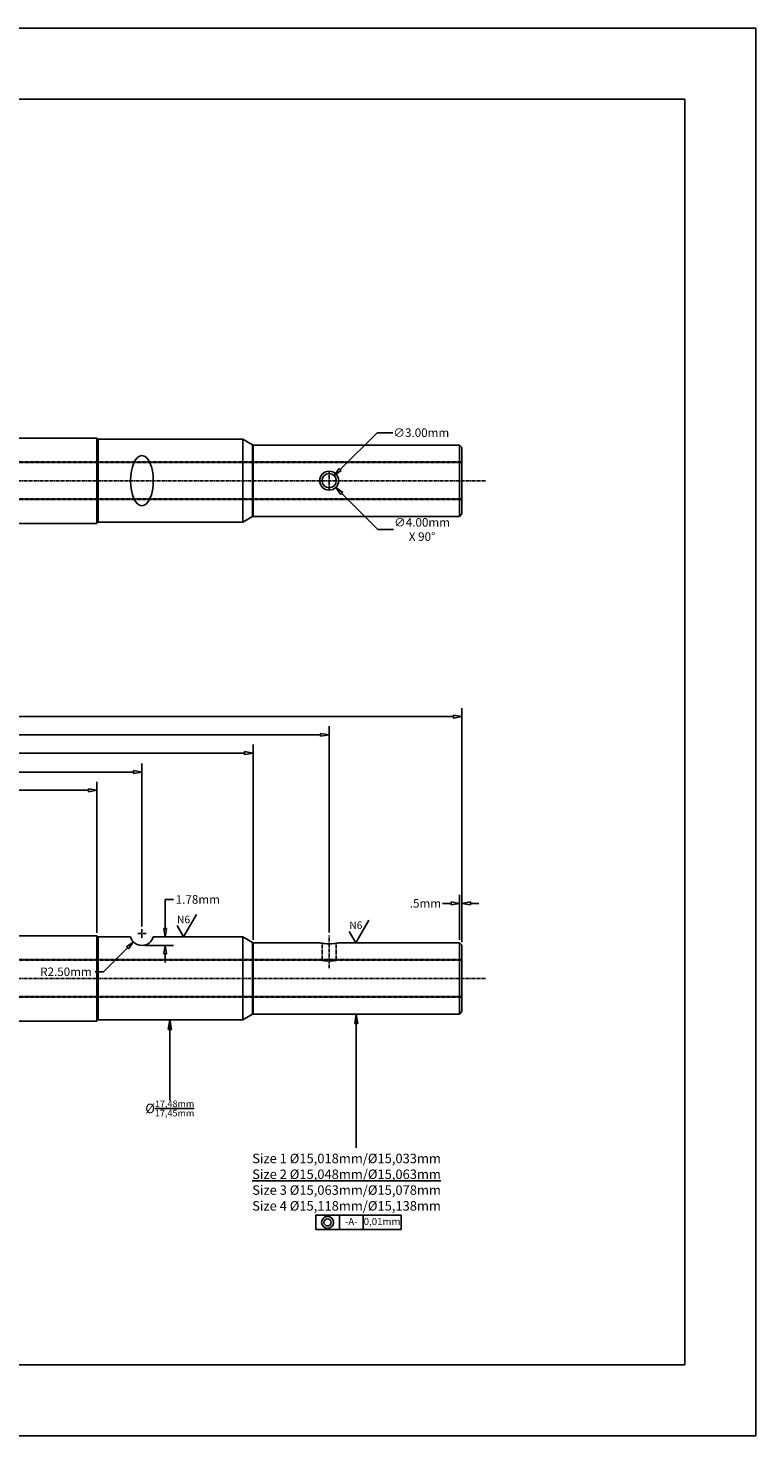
# Model space of a CAD drawing. Units: inches. Extents: x 0 to 420, y 0 to 297.
# Drawn here: x 266 to 420, y 0 to 297 of the extents above; entities that cross this region are included whole.
import ezdxf
from ezdxf.enums import TextEntityAlignment as Align

# ---------------------------------------------------------------- set-up
doc = ezdxf.new("R2010")
doc.units = ezdxf.units.IN
doc.header["$MEASUREMENT"] = 0
doc.linetypes.add('CENTER2', pattern=[1.125, 0.75, -0.125, 0.125, -0.125])
doc.linetypes.add('HIDDEN2', pattern=[0.1875, 0.125, -0.0625])
for name, color, linetype in [('CENTER', 1, 'CENTER2'), ('CENTERLINE', 1, 'CENTER2'), ('HIDDEN', 5, 'HIDDEN2'), ('TEXT', 5, 'Continuous')]:
    doc.layers.add(name, color=color, linetype=linetype)
doc.dimstyles.get("Standard").update_dxf_attribs({"dimscale": 10, "dimtxt": 0.18, "dimasz": 0.18, "dimexe": 0.18, "dimexo": 0.0625, "dimgap": 0.09, "dimtad": 0, "dimtih": 1, "dimtoh": 1, "dimdec": 4, "dimzin": 0, "dimdsep": 46, "dimtxsty": 'Standard', "dimblk": 'CLOSEDBLANK', "dimcen": 0.09, "dimadec": 4, "dimazin": 0, "dimtfac": 1, "dimtdec": 4, "dimtofl": 0, "dimtmove": 0, "dimatfit": 3, "dimldrblk": 'CLOSEDBLANK', "dimfxl": 0, "dimtolj": 1, "dimtzin": 0, "dimarcsym": 0})
doc.dimstyles.new('Standard$0', dxfattribs={"dimscale": 10, "dimtxt": 0.18, "dimasz": 0.18, "dimexe": 0.18, "dimexo": 0.0625, "dimgap": 0.09, "dimtad": 0, "dimtih": 1, "dimtoh": 1, "dimdec": 4, "dimzin": 4, "dimdsep": 46, "dimtxsty": 'Standard', "dimblk": 'CLOSEDBLANK', "dimcen": 0.09, "dimadec": 5, "dimazin": 1, "dimtfac": 1, "dimtdec": 4, "dimtofl": 0, "dimtmove": 0, "dimatfit": 3, "dimldrblk": 'CLOSEDBLANK', "dimfxl": 0, "dimtolj": 1, "dimtzin": 0, "dimarcsym": 0})

# ---------------------------------------------------------------- blocks, each defined once
blk = doc.blocks.new('_ClosedBlank')
at = {"color": 0, "linetype": 'ByBlock', "lineweight": -2}
for p, q in [((-1, 0.17), (0, 0)), ((-1, 0.17), (-1, -0.17)), ((0, 0), (-1, -0.17))]:
    blk.add_line(p, q, dxfattribs=at)
blk = doc.blocks.new('*D12')
at = {"color": 0, "lineweight": -2}
for p, q in [((104, 108.07), (104, 138)), ((281, 106.15), (281, 138)), ((105.8, 136.2), (186.65, 136.2)), ((279.2, 136.2), (198.35, 136.2))]:
    blk.add_line(p, q, dxfattribs=at)
at = {"layer": 'Defpoints', "color": 0}
for p in [(104, 136.2), (104, 107.45), (281, 105.53)]:
    blk.add_point(p, dxfattribs=at)
at = {"color": 0, "lineweight": -2, "xscale": 1.8, "yscale": 1.8, "zscale": 1.8, "rotation": 180}
blk.add_blockref('_ClosedBlank', (104, 136.2), dxfattribs=at)
at = {"color": 0, "lineweight": -2, "xscale": 1.8, "yscale": 1.8, "zscale": 1.8}
blk.add_blockref('_ClosedBlank', (281, 136.2), dxfattribs=at)
at = {"color": 0, "insert": (192.5, 136.2), "char_height": 1.8, "attachment_point": 5}
blk.add_mtext('\\A1;177.0mm', dxfattribs=at)
blk = doc.blocks.new('*D13')
at = {"color": 0, "lineweight": -2}
for p, q in [((104, 108.07), (104, 145.85)), ((313.94, 104.68), (313.94, 145.85)), ((105.8, 144.05), (202.82, 144.05)), ((312.14, 144.05), (215.12, 144.05))]:
    blk.add_line(p, q, dxfattribs=at)
at = {"layer": 'Defpoints', "color": 0}
for p in [(104, 144.05), (104, 107.45), (313.94, 104.05)]:
    blk.add_point(p, dxfattribs=at)
at = {"color": 0, "lineweight": -2, "xscale": 1.8, "yscale": 1.8, "zscale": 1.8, "rotation": 180}
blk.add_blockref('_ClosedBlank', (104, 144.05), dxfattribs=at)
at = {"color": 0, "lineweight": -2, "xscale": 1.8, "yscale": 1.8, "zscale": 1.8}
blk.add_blockref('_ClosedBlank', (313.94, 144.05), dxfattribs=at)
at = {"color": 0, "insert": (208.97, 144.05), "char_height": 1.8, "attachment_point": 5}
blk.add_mtext('\\A1;209.9mm', dxfattribs=at)
blk = doc.blocks.new('*D14')
at = {"color": 0, "lineweight": -2}
for p, q in [((357.5, 104.68), (357.5, 114.14)), ((358, 104.18), (358, 114.14)), ((355.7, 112.34), (353.9, 112.34)), ((359.8, 112.34), (361.6, 112.34))]:
    blk.add_line(p, q, dxfattribs=at)
at = {"layer": 'Defpoints', "color": 0}
for p in [(357.5, 112.34), (357.5, 104.05), (358, 103.55)]:
    blk.add_point(p, dxfattribs=at)
at = {"color": 0, "lineweight": -2, "xscale": 1.8, "yscale": 1.8, "zscale": 1.8}
blk.add_blockref('_ClosedBlank', (357.5, 112.34), dxfattribs=at)
at = {"color": 0, "lineweight": -2, "xscale": 1.8, "yscale": 1.8, "zscale": 1.8, "rotation": 180}
blk.add_blockref('_ClosedBlank', (358, 112.34), dxfattribs=at)
at = {"color": 0, "insert": (350.3, 112.34), "char_height": 1.8, "attachment_point": 5}
blk.add_mtext('\\A1;.5mm', dxfattribs=at)
blk = doc.blocks.new('*D18')
at = {"color": 0, "lineweight": -2}
for p, q in [((104, 108.07), (104, 149.7)), ((330, 106.18), (330, 149.7)), ((105.8, 147.9), (210.85, 147.9)), ((328.2, 147.9), (223.15, 147.9))]:
    blk.add_line(p, q, dxfattribs=at)
at = {"layer": 'Defpoints', "color": 0}
for p in [(104, 147.9), (104, 107.45), (330, 105.55)]:
    blk.add_point(p, dxfattribs=at)
at = {"color": 0, "lineweight": -2, "xscale": 1.8, "yscale": 1.8, "zscale": 1.8, "rotation": 180}
blk.add_blockref('_ClosedBlank', (104, 147.9), dxfattribs=at)
at = {"color": 0, "lineweight": -2, "xscale": 1.8, "yscale": 1.8, "zscale": 1.8}
blk.add_blockref('_ClosedBlank', (330, 147.9), dxfattribs=at)
at = {"color": 0, "insert": (217, 147.9), "char_height": 1.8, "attachment_point": 5}
blk.add_mtext('\\A1;226.0mm', dxfattribs=at)
blk = doc.blocks.new('*D19')
at = {"color": 0, "lineweight": -2}
for p, q in [((104, 108.07), (104, 153.55)), ((105.8, 151.75), (224.85, 151.75)), ((356.2, 151.75), (237.15, 151.75)), ((358, 104.18), (358, 153.55))]:
    blk.add_line(p, q, dxfattribs=at)
at = {"layer": 'Defpoints', "color": 0}
for p in [(104, 151.75), (104, 107.45), (358, 103.55)]:
    blk.add_point(p, dxfattribs=at)
at = {"color": 0, "lineweight": -2, "xscale": 1.8, "yscale": 1.8, "zscale": 1.8, "rotation": 180}
blk.add_blockref('_ClosedBlank', (104, 151.75), dxfattribs=at)
at = {"color": 0, "lineweight": -2, "xscale": 1.8, "yscale": 1.8, "zscale": 1.8}
blk.add_blockref('_ClosedBlank', (358, 151.75), dxfattribs=at)
at = {"color": 0, "insert": (231, 151.75), "char_height": 1.8, "attachment_point": 5}
blk.add_mtext('\\A1;254.0mm', dxfattribs=at)
blk = doc.blocks.new('*D20')
at = {"color": 0, "lineweight": -2}
for p, q in [((104, 106.05), (104, 141.85)), ((105.8, 140.05), (191.25, 140.05)), ((288.7, 140.05), (203.25, 140.05)), ((290.5, 107.47), (290.5, 141.85))]:
    blk.add_line(p, q, dxfattribs=at)
at = {"layer": 'Defpoints', "color": 0}
for p in [(104, 140.05), (104, 105.43), (290.5, 106.85)]:
    blk.add_point(p, dxfattribs=at)
at = {"color": 0, "lineweight": -2, "xscale": 1.8, "yscale": 1.8, "zscale": 1.8, "rotation": 180}
blk.add_blockref('_ClosedBlank', (104, 140.05), dxfattribs=at)
at = {"color": 0, "lineweight": -2, "xscale": 1.8, "yscale": 1.8, "zscale": 1.8}
blk.add_blockref('_ClosedBlank', (290.5, 140.05), dxfattribs=at)
at = {"color": 0, "insert": (197.25, 140.05), "char_height": 1.8, "attachment_point": 5}
blk.add_mtext('\\A1;186.5mm', dxfattribs=at)
blk = doc.blocks.new('*D21')
at = {"color": 0, "lineweight": -2}
for p, q in [((295.39, 107.07), (295.39, 113.17)), ((295.39, 113.17), (297.19, 113.17)), ((293.54, 105.27), (297.19, 105.27)), ((291.12, 103.49), (297.19, 103.49)), ((295.39, 101.69), (295.39, 99.89))]:
    blk.add_line(p, q, dxfattribs=at)
at = {"layer": 'Defpoints', "color": 0}
for p in [(292.91, 105.27), (295.39, 105.27), (290.5, 103.49)]:
    blk.add_point(p, dxfattribs=at)
at = {"color": 0, "lineweight": -2, "xscale": 1.8, "yscale": 1.8, "zscale": 1.8}
for p, rotation in [((295.39, 105.27), 270), ((295.39, 103.49), 90)]:
    blk.add_blockref('_ClosedBlank', p, dxfattribs=dict(at, rotation=rotation))
at = {"color": 0, "insert": (302.29, 113.17), "char_height": 1.8, "attachment_point": 5}
blk.add_mtext('\\A1;1.78mm', dxfattribs=at)
blk = doc.blocks.new('*D22')
at = {"color": 0, "lineweight": -2}
for p, q in [((282.42, 97.91), (287.46, 102.95)), ((280.62, 97.91), (282.42, 97.91))]:
    blk.add_line(p, q, dxfattribs=at)
at = {"layer": 'Defpoints', "color": 0}
for p in [(288.73, 104.22), (290.5, 105.99)]:
    blk.add_point(p, dxfattribs=at)
at = {"color": 0, "lineweight": -2, "xscale": 1.8, "yscale": 1.8, "zscale": 1.8, "rotation": 44.99999999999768}
blk.add_blockref('_ClosedBlank', (288.73, 104.22), dxfattribs=at)
at = {"color": 0, "insert": (274.47, 97.91), "char_height": 1.8, "attachment_point": 5}
blk.add_mtext('\\A1;R2.50mm', dxfattribs=at)
blk = doc.blocks.new('*D23')
at = {"color": 0, "lineweight": -2}
for p, q in [((340.13, 211.65), (332.33, 203.86)), ((343.43, 211.65), (340.13, 211.65))]:
    blk.add_line(p, q, dxfattribs=at)
at = {"layer": 'Defpoints', "color": 0}
for p in [(331.06, 202.59), (328.94, 200.46)]:
    blk.add_point(p, dxfattribs=at)
at = {"color": 0, "lineweight": -2, "xscale": 1.8, "yscale": 1.8, "zscale": 1.8, "rotation": 225}
blk.add_blockref('_ClosedBlank', (331.06, 202.59), dxfattribs=at)
at = {"color": 0, "insert": (349.43, 211.65), "char_height": 1.8, "attachment_point": 5}
blk.add_mtext('\\A1;∅3.00mm', dxfattribs=at)
blk = doc.blocks.new('*D24')
at = {"color": 0, "lineweight": -2}
for p, q in [((340.29, 191.23), (332.69, 198.84)), ((343.59, 191.23), (340.29, 191.23))]:
    blk.add_line(p, q, dxfattribs=at)
at = {"layer": 'Defpoints', "color": 0}
for p in [(328.59, 202.94), (331.41, 200.11)]:
    blk.add_point(p, dxfattribs=at)
at = {"color": 0, "lineweight": -2, "xscale": 1.8, "yscale": 1.8, "zscale": 1.8, "rotation": 135.0000000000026}
blk.add_blockref('_ClosedBlank', (331.41, 200.11), dxfattribs=at)
at = {"color": 0, "insert": (349.59, 191.23), "char_height": 1.8, "attachment_point": 5}
blk.add_mtext('\\A1;∅4.00mm\\PX 90%%d', dxfattribs=at)

msp = doc.modelspace()

# ---------------------------------------------------------------- linework, layer by layer
for p, q in [((163.99992, 210.52506), (280.99992, 210.52506)), ((280.99992, 192.52506), (280.99992, 210.52506)), ((281.24992, 210.26506), (281.24992, 192.78506)), ((281.24992, 210.26506), (311.76787, 210.26506)), ((311.76787, 192.78506), (311.76787, 210.26506)), ((311.76787, 210.26506), (313.8143, 209.08355)), ((313.8143, 193.96656), (313.8143, 209.08355)), ((313.9393, 209.05006), (357.49992, 209.05006)), ((313.9393, 194.00006), (313.9393, 209.05006)), ((357.49992, 209.05006), (357.99992, 208.55006)), ((357.49992, 194.00006), (357.49992, 209.05006)), ((357.99992, 194.50006), (357.99992, 208.55006)), ((311.76787, 192.78506), (313.8143, 193.96656)), ((313.9393, 194.00006), (357.49992, 194.00006)), ((357.49992, 194.00006), (357.99992, 194.50006)), ((163.99992, 192.52506), (280.99992, 192.52506)), ((281.24992, 192.78506), (311.76912, 192.78506)), ((299.2805, 105.26506), (302.03013, 110.02756)), ((297.90568, 107.64631), (299.2805, 105.26506)), ((335.61595, 104.05006), (338.36558, 108.81256)), ((163.99992, 105.52506), (280.99992, 105.52506)), ((280.99992, 87.52506), (280.99992, 105.52506)), ((281.24992, 105.26506), (281.24992, 87.78506)), ((281.24992, 105.26506), (288.10645, 105.26506)), ((292.89339, 105.26506), (311.76787, 105.26506)), ((311.76787, 87.78506), (311.76787, 105.26506)), ((311.76787, 105.26506), (313.8143, 104.08355)), ((313.8143, 88.96656), (313.8143, 104.08355)), ((313.9393, 104.05006), (327.9999, 104.05006)), ((313.9393, 89.00006), (313.9393, 104.05006)), ((331.9999, 104.05006), (357.49992, 104.05006)), ((334.24113, 106.43131), (335.61595, 104.05006)), ((357.49992, 104.05006), (357.99992, 103.55006)), ((357.49992, 89.00006), (357.49992, 104.05006)), ((357.99992, 89.50006), (357.99992, 103.55006)), ((357.49992, 89.00006), (357.99992, 89.50006)), ((163.99992, 87.52506), (280.99992, 87.52506)), ((281.24992, 87.78506), (311.76912, 87.78506)), ((311.76787, 87.78506), (313.8143, 88.96656)), ((313.9393, 89.00006), (357.49992, 89.00006))]:
    msp.add_line(p, q)
for points in [[(0.00001, 0), (420.00001, 0), (420.00001, 297), (0.00001, 297)], [(15.00001, 15), (405.00001, 15), (405.00001, 282), (15.00001, 282)]]:
    msp.add_lwpolyline(points, close=True)
for radius in [2, 1.5]:
    msp.add_circle((329.9999, 201.52506), radius)
for centre, radius, start, end in [((281.24992, 210.51506), 0.25, 180, 270), ((313.9393, 209.30006), 0.25, 240, 270), ((313.9393, 193.75006), 0.25, 90, 120), ((281.24992, 192.53506), 0.25, 90, 180), ((281.24992, 105.51506), 0.25, 180, 270), ((290.49992, 105.98706), 2.5, 196.7861274, 343.2138726), ((313.9393, 104.30006), 0.25, 240, 270), ((329.9999, 111.30441), 7.525, 254.5866509, 285.4133491), ((281.24992, 87.53506), 0.25, 90, 180), ((313.9393, 88.75006), 0.25, 90, 120)]:
    msp.add_arc(centre, radius, start, end)
msp.add_ellipse((290.49992, 201.52506), major_axis=(0, -5.28376), ratio=0.452986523)
at = {"layer": 'CENTER'}
for p, q in [((329.9999, 199.52506), (329.9999, 203.52506)), ((289.59992, 105.98706), (291.39992, 105.98706)), ((290.49992, 105.08706), (290.49992, 106.88706)), ((329.9999, 98.68266), (329.9999, 105.55006))]:
    msp.add_line(p, q, dxfattribs=at)
at = {"layer": 'CENTERLINE'}
for p, q in [((98.99992, 201.52506), (362.99992, 201.52506)), ((98.99992, 96.52506), (362.99992, 96.52506))]:
    msp.add_line(p, q, dxfattribs=at)
at = {"layer": 'HIDDEN'}
for p, q in [((138.58246, 205.48746), (357.99992, 205.48746)), ((138.73486, 205.33506), (357.99992, 205.33506)), ((138.58252, 197.56266), (357.99992, 197.56266)), ((138.73492, 197.71506), (357.99992, 197.71506)), ((327.9999, 104.05006), (328.4999, 103.84295)), ((331.9999, 104.05006), (331.4999, 103.84295)), ((328.4999, 100.33506), (328.4999, 103.84295)), ((328.4999, 103.84295), (329.02407, 103.84295)), ((330.97574, 103.84295), (331.4999, 103.84295)), ((331.4999, 100.33506), (331.4999, 103.84295)), ((138.58246, 100.48746), (357.99992, 100.48746)), ((138.73486, 100.33506), (357.99992, 100.33506)), ((138.58252, 92.56266), (357.99992, 92.56266)), ((138.73492, 92.71506), (357.99992, 92.71506))]:
    msp.add_line(p, q, dxfattribs=at)
msp.add_ellipse((329.9999, 100.33506), major_axis=(-1.5, 0), ratio=0.1016, start_param=0, end_param=3.141592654, dxfattribs=at)
at = {"layer": 'TEXT', "color": 7}
for p, q in [((327.15422, 43.52503), (327.15422, 46.52503)), ((327.15422, 46.52503), (332.15422, 46.52503)), ((332.15422, 46.52503), (337.15422, 46.52503)), ((332.15422, 43.52503), (332.15422, 46.52503)), ((337.15422, 46.52503), (345.15422, 46.52503)), ((337.15422, 43.52503), (337.15422, 46.52503)), ((345.15422, 43.52503), (345.15422, 46.52503)), ((327.15422, 43.52503), (332.15422, 43.52503)), ((332.15422, 43.52503), (337.15422, 43.52503)), ((337.15422, 43.52503), (345.15422, 43.52503))]:
    msp.add_line(p, q, dxfattribs=at)
for radius in [1.25, 0.75]:
    msp.add_circle((329.65422, 45.02503), radius, dxfattribs=at)

# ---------------------------------------------------------------- texts
for p in [(299.2805, 107.64631), (335.61595, 106.43131)]:
    msp.add_text('N6', height=1.5875).set_placement(p, align=Align.BOTTOM_CENTER)
at = {"insert": (296.37429, 70.75006), "char_height": 2, "width": 10.5482646, "attachment_point": 2}
msp.add_mtext('\\A1;%%C{\\H0.7x;\\S17,48mm/17,45mm;}', dxfattribs=at)
at = {"layer": 'TEXT', "color": 7}
for s, insert, char_height, width, attachment_point in [('\\A1;Size 1 %%C15,018mm/%%C15,033mm\\P{\\LSize 2 %%C15,048mm/%%C15,063mm}\\PSize 3 %%C15,063mm/%%C15,078mm\\PSize 4 %%C15,118mm/%%C15,138mm', (313.76279, 59.52503), 2, 48.5376086, 1), ('-A-', (334.65422, 45.02503), 1.5, 1.19634, 5), ('0,01mm', (341.15422, 45.02503), 1.5, 6.6720954, 5)]:
    msp.add_mtext(s, dxfattribs=dict(at, insert=insert, char_height=char_height, width=width, attachment_point=attachment_point))

# ---------------------------------------------------------------- dimensions: what is measured, and where the dimension line sits
dim = msp.add_diameter_dim_2p(p1=(328.93924, 200.4644), p2=(331.06056, 202.58572), dimstyle='Standard', override={"dimdec": 2, "dimpost": 'mm', "dimcen": 0})
dim.commit()
dim.dimension.update_dxf_attribs({"geometry": '*D23', "text_midpoint": (349.42588, 211.65104), "dimtype": 163})
dim = msp.add_diameter_dim_2p(p1=(328.58569, 202.93927), p2=(331.41411, 200.11084), text='<>\\PX 90%%d', dimstyle='Standard', override={"dimdec": 2, "dimpost": 'mm', "dimcen": 0})
dim.commit()
dim.dimension.update_dxf_attribs({"geometry": '*D24', "text_midpoint": (349.59047, 191.23449), "dimtype": 163})
for base, p1, p2, picture, middle in [((103.99992, 151.75006), (357.99992, 103.55006), (103.99992, 107.44614), '*D19', (230.99992, 151.75006)), ((103.99992, 147.90006), (329.9999, 105.55006), (103.99992, 107.44614), '*D18', (216.99991, 147.90006)), ((103.99992, 144.05006), (313.9393, 104.05006), (103.99992, 107.44614), '*D13', (208.96961, 144.05006)), ((103.99992, 140.05006), (290.49992, 106.84706), (103.99992, 105.42506), '*D20', (197.24992, 140.05006)), ((103.99992, 136.20006), (280.99992, 105.52506), (103.99992, 107.44614), '*D12', (192.49992, 136.20006))]:
    dim = msp.add_linear_dim(base=base, p1=p1, p2=p2, dimstyle='Standard$0', override={"dimscale": 10, "dimdec": 1, "dimpost": 'mm', "dimblk1": 'ClosedBlank', "dimblk2": 'ClosedBlank', "dimsah": 1})
    dim.commit()
    dim.dimension.update_dxf_attribs({"geometry": picture, "text_midpoint": middle})
dim = msp.add_linear_dim(base=(295.38762, 105.26506), p1=(290.49992, 103.48706), p2=(292.91475, 105.26506), angle=90, dimstyle='Standard$0', override={"dimdec": 2, "dimpost": 'mm'})
dim.commit()
dim.dimension.update_dxf_attribs({"geometry": '*D21', "text_midpoint": (302.28762, 113.16875), "dimtype": 160})
dim = msp.add_linear_dim(base=(357.49992, 112.3439), p1=(357.99992, 103.55006), p2=(357.49992, 104.05006), angle=180, dimstyle='Standard$0', override={"dimscale": 10, "dimdec": 1, "dimpost": 'mm', "dimblk1": 'ClosedBlank', "dimblk2": 'ClosedBlank', "dimsah": 1})
dim.commit()
dim.dimension.update_dxf_attribs({"geometry": '*D14', "text_midpoint": (350.29992, 112.3439)})
dim = msp.add_radius_dim(center=(290.49992, 105.98706), mpoint=(288.73215, 104.21929), dimstyle='Standard', override={"dimdec": 2, "dimpost": 'mm', "dimcen": 0})
dim.commit()
dim.dimension.update_dxf_attribs({"geometry": '*D22', "text_midpoint": (274.47484, 97.91197), "dimtype": 164})

# ---------------------------------------------------------------- leaders
msp.add_leader([(296.37429, 87.75006), (296.37429, 70.75006)], dimstyle='Standard', override={"dimscale": 1, "dimasz": 2, "dimgap": 0.09, "dimtad": 0, "dimldrblk": 'ClosedBlank'})
msp.add_leader([(335.71961, 89.00006), (335.71961, 60.76404)], dimstyle='Standard', override={"dimscale": 1, "dimasz": 2, "dimgap": 0.09, "dimtad": 0, "dimldrblk": 'ClosedBlank'}, dxfattribs=at)

doc.saveas('drawing.dxf')
